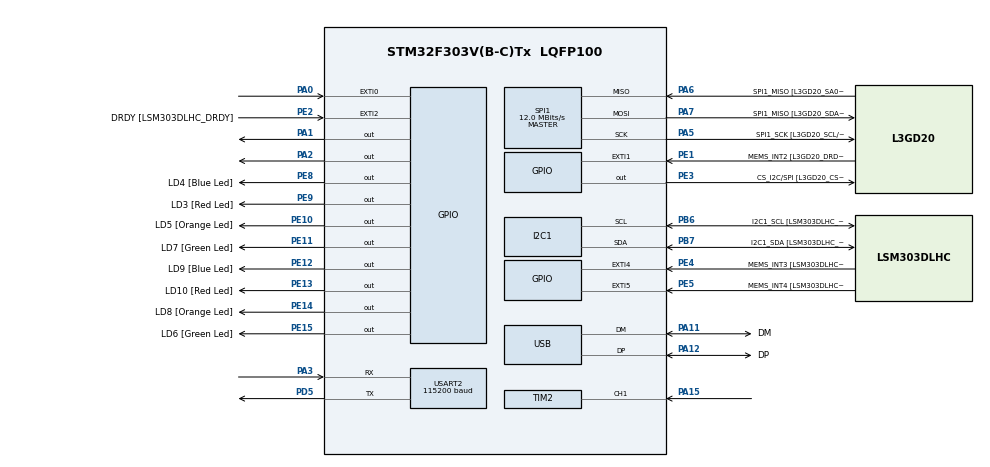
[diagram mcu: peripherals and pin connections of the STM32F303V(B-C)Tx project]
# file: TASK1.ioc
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I2C1.Timing=0x2000090E
I2C1.Timing-I2C=0x2000090E
Mcu.Family=STM32F3
Mcu.Name=STM32F303V(B-C)Tx
Mcu.Package=LQFP100
NVIC.EXTI0_IRQn=true\:0\:0\:false\:false\:true\:true\:true\:true
NVIC.PriorityGroup=NVIC_PRIORITYGROUP_0
PA0.Signal=GPXTI0
PA1.Signal=GPIO_Output
PA11.GPIO_Label=DM
PA11.Mode=Device
PA11.Signal=USB_DM
PA12.GPIO_Label=DP
PA12.Mode=Device
PA12.Signal=USB_DP
PA13.GPIO_Label=SWDIO
PA13.Mode=Serial_Wire
PA13.Signal=SYS_JTMS-SWDIO
PA14.GPIO_Label=SWCLK
PA14.Mode=Serial_Wire
PA14.Signal=SYS_JTCK-SWCLK
PA15.Signal=S_TIM2_CH1_ETR
PA2.Signal=GPIO_Output
PA3.Mode=Asynchronous
PA3.Signal=USART2_RX
PA5.GPIO_Label=SPI1_SCK [L3GD20_SCL/SPC]
PA5.Mode=Full_Duplex_Master
PA5.Signal=SPI1_SCK
PA6.GPIO_Label=SPI1_MISO [L3GD20_SA0/SDO]
PA6.Mode=Full_Duplex_Master
PA6.Signal=SPI1_MISO
PA7.GPIO_Label=SPI1_MISO [L3GD20_SDA/SDI/SDO]
PA7.Mode=Full_Duplex_Master
PA7.Signal=SPI1_MOSI
PB3.GPIO_Label=SWO
PB3.Signal=SYS_JTDO-TRACESWO
PB6.GPIO_Label=I2C1_SCL [LSM303DLHC_SCL]
PB6.GPIO_Pu=GPIO_PULLUP
PB6.Mode=I2C
PB6.Signal=I2C1_SCL
PB7.GPIO_Label=I2C1_SDA [LSM303DLHC_SDA]
PB7.GPIO_Pu=GPIO_PULLUP
PB7.Mode=I2C
PB7.Signal=I2C1_SDA
PC14-OSC32_IN.GPIO_Label=OSC32_IN
PC14-OSC32_IN.Signal=RCC_OSC32_IN
PC15-OSC32_OUT.GPIO_Label=OSC32_OUT
PC15-OSC32_OUT.Signal=RCC_OSC32_OUT
PD5.Mode=Asynchronous
PD5.Signal=USART2_TX
PE1.GPIO_Label=MEMS_INT2 [L3GD20_DRDY/INT2]
PE1.GPIO_ModeDefaultEXTI=GPIO_MODE_EVT_RISING
PE1.Signal=GPXTI1
PE10.GPIO_Label=LD5 [Orange Led]
PE10.Signal=GPIO_Output
PE11.GPIO_Label=LD7 [Green Led]
PE11.Signal=GPIO_Output
PE12.GPIO_Label=LD9 [Blue Led]
PE12.Signal=GPIO_Output
PE13.GPIO_Label=LD10 [Red Led]
PE13.Signal=GPIO_Output
PE14.GPIO_Label=LD8 [Orange Led]
PE14.Signal=GPIO_Output
PE15.GPIO_Label=LD6 [Green Led]
PE15.Signal=GPIO_Output
PE2.GPIO_Label=DRDY [LSM303DLHC_DRDY]
PE2.GPIO_ModeDefaultEXTI=GPIO_MODE_EVT_RISING
PE2.Signal=GPXTI2
PE3.GPIO_Label=CS_I2C/SPI [L3GD20_CS_I2C/SPI]
PE3.Signal=GPIO_Output
PE4.GPIO_Label=MEMS_INT3 [LSM303DLHC_INT1]
PE4.GPIO_ModeDefaultEXTI=GPIO_MODE_EVT_RISING
PE4.Signal=GPXTI4
PE5.GPIO_Label=MEMS_INT4 [LSM303DLHC_INT2]
PE5.GPIO_ModeDefaultEXTI=GPIO_MODE_EVT_RISING
PE5.Signal=GPXTI5
PE8.GPIO_Label=LD4 [Blue Led]
PE8.Signal=GPIO_Output
PE9.GPIO_Label=LD3 [Red Led]
PE9.Signal=GPIO_Output
PF0-OSC_IN.GPIO_Label=OSC_IN
PF0-OSC_IN.Mode=HSE-External-Clock-Source
PF0-OSC_IN.Signal=RCC_OSC_IN
PF1-OSC_OUT.GPIO_Label=OSC_OUT
PF1-OSC_OUT.Signal=RCC_OSC_OUT
ProjectManager.HeapSize=0x200
ProjectManager.StackSize=0x400
ProjectManager.TargetToolchain=CMake
RCC.AHBFreq_Value=48000000
RCC.APB1CLKDivider=RCC_HCLK_DIV2
RCC.APB1Freq_Value=24000000
RCC.APB1TimFreq_Value=48000000
RCC.APB2Freq_Value=48000000
RCC.APB2TimFreq_Value=48000000
RCC.CortexFreq_Value=48000000
RCC.HCLKFreq_Value=48000000
RCC.HSE_VALUE=8000000
RCC.HSI_VALUE=8000000
RCC.LSE_VALUE=32768
RCC.PLLMUL=RCC_PLL_MUL6
RCC.SYSCLKFreq_VALUE=48000000
RCC.SYSCLKSourceVirtual=RCC_SYSCLKSOURCE_PLLCLK
RCC.USBFreq_Value=48000000
SH.S_TIM2_CH1_ETR.0=TIM2_CH1,Input_Capture1_from_TI1
SPI1.BaudRatePrescaler=SPI_BAUDRATEPRESCALER_4
SPI1.BaudRatePrescaler-Full_Duplex_Master=SPI_BAUDRATEPRESCALER_2
SPI1.CalculateBaudRate=12.0 MBits/s
SPI1.CalculateBaudRate-Full_Duplex_Master=24.0 MBits/s
SPI1.Direction=SPI_DIRECTION_2LINES
SPI1.Mode=SPI_MODE_MASTER
SPI1.Mode-Full_Duplex_Master=SPI_MODE_MASTER
SPI1.VirtualType=VM_MASTER
TIM2.Channel-Input_Capture1_from_TI1=TIM_CHANNEL_1
TIM2.Period=65535
TIM2.Prescaler=47
USART2.BaudRate=115200
USART2.VirtualMode-Asynchronous=VM_ASYNC
board=STM32F3DISCOVERY

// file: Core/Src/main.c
/* USER CODE BEGIN Header */
/**
 ******************************************************************************
 * @file           : main.c
 * @brief          : Lab 06 Task 2 - Frequency Measurement using Input Capture
 ******************************************************************************
 */
/* USER CODE END Header */
#include "main.h"
#include <stdio.h>
#include <string.h>
#include <stdarg.h>

I2C_HandleTypeDef hi2c1;
SPI_HandleTypeDef hspi1;
TIM_HandleTypeDef htim2;
UART_HandleTypeDef huart2;
PCD_HandleTypeDef hpcd_USB_FS;

/* USER CODE BEGIN PV */
volatile uint32_t captureValue = 0;
volatile uint32_t prevCaptureValue = 0;
volatile uint32_t period = 0;
volatile uint8_t captureFlag = 0;
volatile uint8_t firstCapture = 1;
/* USER CODE END PV */

void SystemClock_Config(void);
static void MX_GPIO_Init(void);
static void MX_I2C1_Init(void);
static void MX_SPI1_Init(void);
static void MX_USB_PCD_Init(void);
static void MX_USART2_UART_Init(void);
static void MX_TIM2_Init(void);

/* USER CODE BEGIN 0 */

void print(const char *fmt, ...)
{
  char buffer[128];
  va_list args;
  va_start(args, fmt);
  vsnprintf(buffer, sizeof(buffer), fmt, args);
  va_end(args);
  HAL_UART_Transmit(&huart2, (uint8_t *)buffer, strlen(buffer), HAL_MAX_DELAY);
}

/**
 * @brief Input Capture Callback - measures period between rising edges
 */
void HAL_TIM_IC_CaptureCallback(TIM_HandleTypeDef *htim)
{
  if(htim->Instance == TIM2 && htim->Channel == HAL_TIM_ACTIVE_CHANNEL_1)
  {
    // Read captured value
    captureValue = HAL_TIM_ReadCapturedValue(htim, TIM_CHANNEL_1);

    if(firstCapture)
    {
      // First capture - just store the value
      prevCaptureValue = captureValue;
      firstCapture = 0;
    }
    else
    {
      // Subsequent captures - calculate period
      if(captureValue >= prevCaptureValue)
      {
        // Normal case - no overflow
        period = captureValue - prevCaptureValue;
      }
      else
      {
        // Timer overflow occurred (TIM2 is 32-bit)
        period = (0xFFFFFFFF - prevCaptureValue) + captureValue + 1;
      }

      prevCaptureValue = captureValue;
      captureFlag = 1; // Signal main loop to process
    }
  }
}

/* USER CODE END 0 */

int main(void)
{
  /* MCU Configuration--------------------------------------------------------*/
  HAL_Init();
  SystemClock_Config();

  /* Initialize all configured peripherals */
  MX_GPIO_Init();
  MX_I2C1_Init();
  MX_SPI1_Init();
  MX_USB_PCD_Init();
  MX_USART2_UART_Init();
  MX_TIM2_Init();

  /* USER CODE BEGIN 2 */
  HAL_Delay(100); // Allow UART to stabilize

  print("\r\n========================================\r\n");
  print("Lab 06 Task 2: Frequency Measurement\r\n");
  print("========================================\r\n");
  print("TIM2 CH1 Input Capture on PA0\r\n");
  print("Prescaler: 71 (1 microsecond tick)\r\n");
  print("Waiting for signal...\r\n\r\n");

  // Start Input Capture with interrupt
  HAL_TIM_IC_Start_IT(&htim2, TIM_CHANNEL_1);
  /* USER CODE END 2 */

  /* Infinite loop */
  /* USER CODE BEGIN WHILE */
  while (1)
  {
    if(captureFlag)
    {
      captureFlag = 0; // Clear flag

      // TIM2 clock frequency after prescaler
      // With prescaler = 71: Timer_Clock = APB1_Timer_Clock / (71+1) = 72MHz / 72 = 1 MHz
      // This gives 1 microsecond per tick as required
      uint32_t timerFreq = 1000000; // 1 MHz (1 microsecond tick)

      // Calculate frequency: F = Timer_Frequency / Period
      double frequency = (double)timerFreq / (double)period;

      // Display result
      print("Frequency: %.2f Hz\r\n", frequency);
    }

    HAL_Delay(10); // Small delay to prevent overwhelming UART
    /* USER CODE END WHILE */
  }
  /* USER CODE END 3 */
}

void SystemClock_Config(void)
{
  RCC_OscInitTypeDef RCC_OscInitStruct = {0};
  RCC_ClkInitTypeDef RCC_ClkInitStruct = {0};
  RCC_PeriphCLKInitTypeDef PeriphClkInit = {0};

  RCC_OscInitStruct.OscillatorType = RCC_OSCILLATORTYPE_HSI|RCC_OSCILLATORTYPE_HSE;
  RCC_OscInitStruct.HSEState = RCC_HSE_BYPASS;
  RCC_OscInitStruct.HSEPredivValue = RCC_HSE_PREDIV_DIV1;
  RCC_OscInitStruct.HSIState = RCC_HSI_ON;
  RCC_OscInitStruct.HSICalibrationValue = RCC_HSICALIBRATION_DEFAULT;
  RCC_OscInitStruct.PLL.PLLState = RCC_PLL_ON;
  RCC_OscInitStruct.PLL.PLLSource = RCC_PLLSOURCE_HSE;
  RCC_OscInitStruct.PLL.PLLMUL = RCC_PLL_MUL9;  // HSE 8MHz * 9 = 72MHz
  if (HAL_RCC_OscConfig(&RCC_OscInitStruct) != HAL_OK)
  {
    Error_Handler();
  }

  RCC_ClkInitStruct.ClockType = RCC_CLOCKTYPE_HCLK|RCC_CLOCKTYPE_SYSCLK
                              |RCC_CLOCKTYPE_PCLK1|RCC_CLOCKTYPE_PCLK2;
  RCC_ClkInitStruct.SYSCLKSource = RCC_SYSCLKSOURCE_PLLCLK;
  RCC_ClkInitStruct.AHBCLKDivider = RCC_SYSCLK_DIV1;
  RCC_ClkInitStruct.APB1CLKDivider = RCC_HCLK_DIV2;  // APB1 = 36MHz, Timer = 72MHz
  RCC_ClkInitStruct.APB2CLKDivider = RCC_HCLK_DIV1;

  if (HAL_RCC_ClockConfig(&RCC_ClkInitStruct, FLASH_LATENCY_2) != HAL_OK)
  {
    Error_Handler();
  }
  PeriphClkInit.PeriphClockSelection = RCC_PERIPHCLK_USB|RCC_PERIPHCLK_USART2
                              |RCC_PERIPHCLK_I2C1;
  PeriphClkInit.Usart2ClockSelection = RCC_USART2CLKSOURCE_PCLK1;
  PeriphClkInit.I2c1ClockSelection = RCC_I2C1CLKSOURCE_HSI;
  PeriphClkInit.USBClockSelection = RCC_USBCLKSOURCE_PLL_DIV1_5;
  if (HAL_RCCEx_PeriphCLKConfig(&PeriphClkInit) != HAL_OK)
  {
    Error_Handler();
  }
}

static void MX_TIM2_Init(void)
{
  TIM_MasterConfigTypeDef sMasterConfig = {0};
  TIM_IC_InitTypeDef sConfigIC = {0};

  /* TIM2 Configuration:
   * Timer Clock = 72 MHz (APB1 timer clock when APB1 prescaler != 1)
   * Prescaler = 71 gives: 72MHz / (71+1) = 1 MHz = 1 microsecond tick
   */
  htim2.Instance = TIM2;
  htim2.Init.Prescaler = 71;  // As per lab requirement
  htim2.Init.CounterMode = TIM_COUNTERMODE_UP;
  htim2.Init.Period = 0xFFFFFFFF;  // TIM2 is 32-bit timer
  htim2.Init.ClockDivision = TIM_CLOCKDIVISION_DIV1;
  htim2.Init.AutoReloadPreload = TIM_AUTORELOAD_PRELOAD_DISABLE;

  if (HAL_TIM_IC_Init(&htim2) != HAL_OK)
  {
    Error_Handler();
  }

  sMasterConfig.MasterOutputTrigger = TIM_TRGO_RESET;
  sMasterConfig.MasterSlaveMode = TIM_MASTERSLAVEMODE_DISABLE;
  if (HAL_TIMEx_MasterConfigSynchronization(&htim2, &sMasterConfig) != HAL_OK)
  {
    Error_Handler();
  }

  /* Input Capture Configuration:
   * - Rising edge detection
   * - Direct input (TI1 mapped to IC1)
   * - No prescaler
   * - No filter
   */
  sConfigIC.ICPolarity = TIM_INPUTCHANNELPOLARITY_RISING;  // Rising edge as required
  sConfigIC.ICSelection = TIM_ICSELECTION_DIRECTTI;
  sConfigIC.ICPrescaler = TIM_ICPSC_DIV1;
  sConfigIC.ICFilter = 0;

  if (HAL_TIM_IC_ConfigChannel(&htim2, &sConfigIC, TIM_CHANNEL_1) != HAL_OK)
  {
    Error_Handler();
  }

  /* Enable TIM2 interrupt */
  HAL_NVIC_SetPriority(TIM2_IRQn, 0, 0);
  HAL_NVIC_EnableIRQ(TIM2_IRQn);
}

static void MX_USART2_UART_Init(void)
{
  huart2.Instance = USART2;
  huart2.Init.BaudRate = 115200;
  huart2.Init.WordLength = UART_WORDLENGTH_8B;
  huart2.Init.StopBits = UART_STOPBITS_1;
  huart2.Init.Parity = UART_PARITY_NONE;
  huart2.Init.Mode = UART_MODE_TX_RX;
  huart2.Init.HwFlowCtl = UART_HWCONTROL_NONE;
  huart2.Init.OverSampling = UART_OVERSAMPLING_16;
  huart2.Init.OneBitSampling = UART_ONE_BIT_SAMPLE_DISABLE;
  huart2.AdvancedInit.AdvFeatureInit = UART_ADVFEATURE_NO_INIT;
  if (HAL_UART_Init(&huart2) != HAL_OK)
  {
    Error_Handler();
  }
}

static void MX_GPIO_Init(void)
{
  GPIO_InitTypeDef GPIO_InitStruct = {0};

  /* GPIO Ports Clock Enable */
  __HAL_RCC_GPIOE_CLK_ENABLE();
  __HAL_RCC_GPIOC_CLK_ENABLE();
  __HAL_RCC_GPIOF_CLK_ENABLE();
  __HAL_RCC_GPIOA_CLK_ENABLE();
  __HAL_RCC_GPIOD_CLK_ENABLE();
  __HAL_RCC_GPIOB_CLK_ENABLE();

  /*Configure GPIO pin Output Level */
  HAL_GPIO_WritePin(GPIOE, CS_I2C_SPI_Pin|LD4_Pin|LD3_Pin|LD5_Pin
                          |LD7_Pin|LD9_Pin|LD10_Pin|LD8_Pin
                          |LD6_Pin, GPIO_PIN_RESET);

  /*Configure GPIO pin Output Level */
  HAL_GPIO_WritePin(GPIOA, GPIO_PIN_1|GPIO_PIN_2, GPIO_PIN_RESET);

  /*Configure GPIO pins : DRDY_Pin MEMS_INT3_Pin MEMS_INT4_Pin MEMS_INT2_Pin */
  GPIO_InitStruct.Pin = DRDY_Pin|MEMS_INT3_Pin|MEMS_INT4_Pin|MEMS_INT2_Pin;
  GPIO_InitStruct.Mode = GPIO_MODE_EVT_RISING;
  GPIO_InitStruct.Pull = GPIO_NOPULL;
  HAL_GPIO_Init(GPIOE, &GPIO_InitStruct);

  /*Configure GPIO pins : CS_I2C_SPI_Pin LD4_Pin LD3_Pin LD5_Pin
                           LD7_Pin LD9_Pin LD10_Pin LD8_Pin LD6_Pin */
  GPIO_InitStruct.Pin = CS_I2C_SPI_Pin|LD4_Pin|LD3_Pin|LD5_Pin
                          |LD7_Pin|LD9_Pin|LD10_Pin|LD8_Pin|LD6_Pin;
  GPIO_InitStruct.Mode = GPIO_MODE_OUTPUT_PP;
  GPIO_InitStruct.Pull = GPIO_NOPULL;
  GPIO_InitStruct.Speed = GPIO_SPEED_FREQ_LOW;
  HAL_GPIO_Init(GPIOE, &GPIO_InitStruct);

  /* CRITICAL: PA0 for TIM2_CH1 Input Capture
   * MUST be configured as Alternate Function!
   * Check your STM32 datasheet for correct AF number
   * For STM32F3: usually GPIO_AF1_TIM2
   * For STM32F4: usually GPIO_AF1_TIM2
   */
  GPIO_InitStruct.Pin = GPIO_PIN_0;
  GPIO_InitStruct.Mode = GPIO_MODE_AF_PP;  // Alternate Function Push-Pull
  GPIO_InitStruct.Pull = GPIO_PULLDOWN;    // Pull-down as per requirement
  GPIO_InitStruct.Speed = GPIO_SPEED_FREQ_HIGH;
  GPIO_InitStruct.Alternate = GPIO_AF1_TIM2;  // Verify in datasheet!
  HAL_GPIO_Init(GPIOA, &GPIO_InitStruct);

  /*Configure GPIO pins : PA1 PA2 */
  GPIO_InitStruct.Pin = GPIO_PIN_1|GPIO_PIN_2;
  GPIO_InitStruct.Mode = GPIO_MODE_OUTPUT_PP;
  GPIO_InitStruct.Pull = GPIO_NOPULL;
  GPIO_InitStruct.Speed = GPIO_SPEED_FREQ_LOW;
  HAL_GPIO_Init(GPIOA, &GPIO_InitStruct);
}

static void MX_I2C1_Init(void)
{
  hi2c1.Instance = I2C1;
  hi2c1.Init.Timing = 0x2000090E;
  hi2c1.Init.OwnAddress1 = 0;
  hi2c1.Init.AddressingMode = I2C_ADDRESSINGMODE_7BIT;
  hi2c1.Init.DualAddressMode = I2C_DUALADDRESS_DISABLE;
  hi2c1.Init.OwnAddress2 = 0;
  hi2c1.Init.OwnAddress2Masks = I2C_OA2_NOMASK;
  hi2c1.Init.GeneralCallMode = I2C_GENERALCALL_DISABLE;
  hi2c1.Init.NoStretchMode = I2C_NOSTRETCH_DISABLE;
  if (HAL_I2C_Init(&hi2c1) != HAL_OK)
  {
    Error_Handler();
  }
  if (HAL_I2CEx_ConfigAnalogFilter(&hi2c1, I2C_ANALOGFILTER_ENABLE) != HAL_OK)
  {
    Error_Handler();
  }
  if (HAL_I2CEx_ConfigDigitalFilter(&hi2c1, 0) != HAL_OK)
  {
    Error_Handler();
  }
}

static void MX_SPI1_Init(void)
{
  hspi1.Instance = SPI1;
  hspi1.Init.Mode = SPI_MODE_MASTER;
  hspi1.Init.Direction = SPI_DIRECTION_2LINES;
  hspi1.Init.DataSize = SPI_DATASIZE_4BIT;
  hspi1.Init.CLKPolarity = SPI_POLARITY_LOW;
  hspi1.Init.CLKPhase = SPI_PHASE_1EDGE;
  hspi1.Init.NSS = SPI_NSS_SOFT;
  hspi1.Init.BaudRatePrescaler = SPI_BAUDRATEPRESCALER_4;
  hspi1.Init.FirstBit = SPI_FIRSTBIT_MSB;
  hspi1.Init.TIMode = SPI_TIMODE_DISABLE;
  hspi1.Init.CRCCalculation = SPI_CRCCALCULATION_DISABLE;
  hspi1.Init.CRCPolynomial = 7;
  hspi1.Init.CRCLength = SPI_CRC_LENGTH_DATASIZE;
  hspi1.Init.NSSPMode = SPI_NSS_PULSE_ENABLE;
  if (HAL_SPI_Init(&hspi1) != HAL_OK)
  {
    Error_Handler();
  }
}

static void MX_USB_PCD_Init(void)
{
  hpcd_USB_FS.Instance = USB;
  hpcd_USB_FS.Init.dev_endpoints = 8;
  hpcd_USB_FS.Init.speed = PCD_SPEED_FULL;
  hpcd_USB_FS.Init.phy_itface = PCD_PHY_EMBEDDED;
  hpcd_USB_FS.Init.low_power_enable = DISABLE;
  hpcd_USB_FS.Init.battery_charging_enable = DISABLE;
  if (HAL_PCD_Init(&hpcd_USB_FS) != HAL_OK)
  {
    Error_Handler();
  }
}

void Error_Handler(void)
{
  __disable_irq();
  while (1)
  {
  }
}
